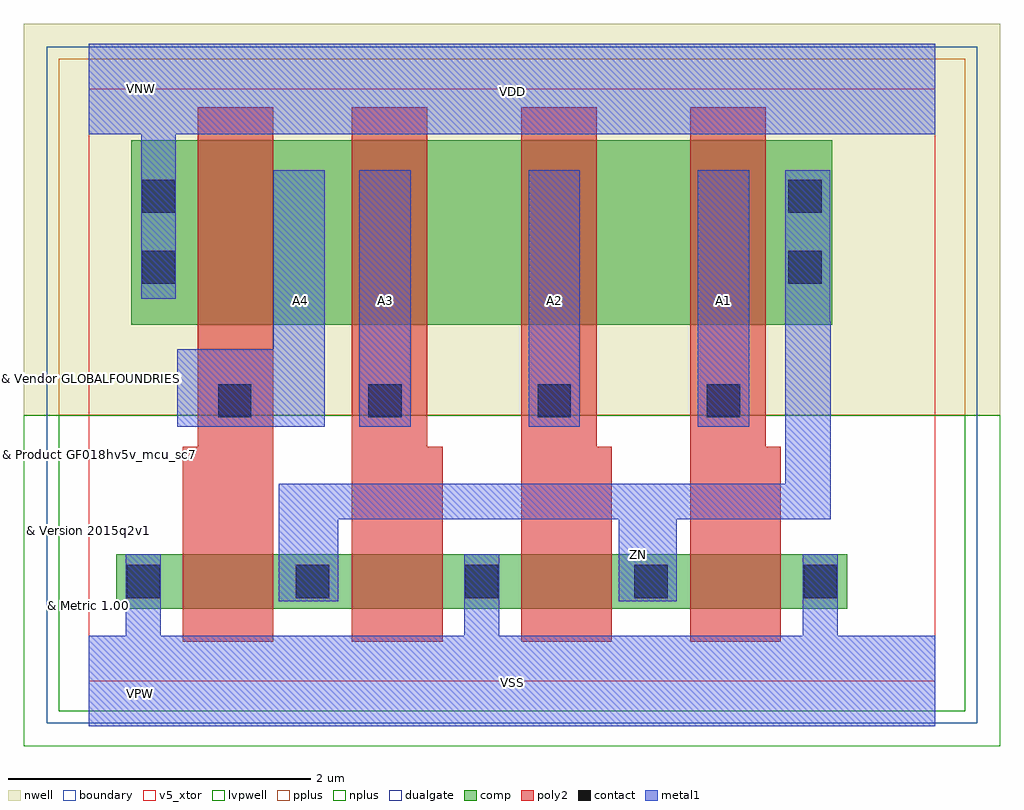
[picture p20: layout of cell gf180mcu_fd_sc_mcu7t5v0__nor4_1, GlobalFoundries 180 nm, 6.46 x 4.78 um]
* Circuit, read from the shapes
.subckt gf180mcu_fd_sc_mcu7t5v0__nor4_1 A1 A2 A3 A4 VDD VNW VSS ZN
XM1 ZN A4 VSS VSUBS nfet_05v0 w=0.36u l=0.6u
XM2 VSS A3 ZN VSUBS nfet_05v0 w=0.36u l=0.6u
XM3 ZN A2 VSS VSUBS nfet_05v0 w=0.36u l=0.6u
XM4 VSS A1 ZN VSUBS nfet_05v0 w=0.36u l=0.6u
XM5 n1 A4 VDD VNW pfet_05v0 w=1.22u l=0.5u
XM6 n2 A3 n1 VNW pfet_05v0 w=1.22u l=0.5u
XM7 n3 A2 n2 VNW pfet_05v0 w=1.22u l=0.5u
XM8 ZN A1 n3 VNW pfet_05v0 w=1.22u l=0.5u
.ends

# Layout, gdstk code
import gdstk
lib = gdstk.Library(unit=1e-6, precision=1e-09)
def R(c, l, rs):  # rectangles x0, y0, x1, y1
    for r in rs: c.add(gdstk.rectangle(r[:2], r[2:], *l))
def A(c, l, x, y, w, h, nx, ny, dx, dy):  # array of equal rectangles
    R(c, l, [(x+i*dx, y+j*dy, x+i*dx+w, y+j*dy+h) for i in range(nx) for j in range(ny)])
def P(c, l, *ps):  # polygons
    for p in ps: c.add(gdstk.Polygon(p, *l))
boundary = (0, 0)
nwell = (21, 0)
comp = (22, 0)
poly2 = (30, 0)
pplus = (31, 0)
nplus = (32, 0)
contact = (33, 0)
metal1 = (34, 0)
dualgate = (55, 0)
v5_xtor = (112, 1)
lvpwell = (204, 0)

gf180mcu_fd_sc_mcu7t5v0_ = lib.new_cell('gf180mcu_fd_sc_mcu7t5v0__nor4_1')
R(gf180mcu_fd_sc_mcu7t5v0_, boundary, [(0,0,5.6,3.92)])
R(gf180mcu_fd_sc_mcu7t5v0_, nwell, [(-0.43,1.76,6.03,4.35)])
R(gf180mcu_fd_sc_mcu7t5v0_, comp, [(0.18,0.48,5.02,0.84), (0.28,2.36,4.92,3.58)])
P(gf180mcu_fd_sc_mcu7t5v0_, poly2, [(0.62,0.26),(0.62,1.55),(0.72,1.55),(0.72,3.8),(1.22,3.8),(1.22,0.26)],
  [(1.74,0.26),(1.74,3.8),(2.24,3.8),(2.24,1.55),(2.34,1.55),(2.34,0.26)],
  [(2.86,0.26),(2.86,3.8),(3.36,3.8),(3.36,1.55),(3.46,1.55),(3.46,0.26)],
  [(3.98,0.26),(3.98,3.8),(4.48,3.8),(4.48,1.55),(4.58,1.55),(4.58,0.26)])
R(gf180mcu_fd_sc_mcu7t5v0_, pplus, [(-0.2,1.76,5.8,4.12)])
R(gf180mcu_fd_sc_mcu7t5v0_, nplus, [(-0.2,-0.2,5.8,1.76)])
A(gf180mcu_fd_sc_mcu7t5v0_, contact, 0.25, 0.55, 0.22, 0.22, 5, 1, 1.12, 0)
A(gf180mcu_fd_sc_mcu7t5v0_, contact, 1.85, 1.745, 0.22, 0.22, 3, 1, 1.12, 0)
R(gf180mcu_fd_sc_mcu7t5v0_, contact, [(0.855,1.745,1.075,1.965), (0.35,2.63,0.57,2.85), (4.63,2.63,4.85,2.85), (0.35,3.1,0.57,3.32), (4.63,3.1,4.85,3.32)])
A(gf180mcu_fd_sc_mcu7t5v0_, metal1, 1.79, 1.685, 0.34, 1.695, 3, 1, 1.12, 0)
P(gf180mcu_fd_sc_mcu7t5v0_, metal1, [(0.585,1.685),(0.585,2.195),(1.22,2.195),(1.22,3.38),(1.56,3.38),(1.56,1.685)],
  [(1.255,0.53),(1.255,1.305),(4.61,1.305),(4.61,3.38),(4.905,3.38),(4.905,2.38),(4.91,2.38),(4.91,1.07),(3.89,1.07),(3.89,0.53),(3.505,0.53),(3.505,1.07),(1.65,1.07),(1.65,0.53)],
  [(0,-0.3),(0,0.3),(0.245,0.3),(0.245,0.84),(0.475,0.84),(0.475,0.3),(2.485,0.3),(2.485,0.84),(2.715,0.84),(2.715,0.3),(4.725,0.3),(4.725,0.84),(4.955,0.84),(4.955,0.3),(5.6,0.3),(5.6,-0.3)],
  [(0.345,2.53),(0.345,3.62),(0,3.62),(0,4.22),(5.6,4.22),(5.6,3.62),(0.575,3.62),(0.575,2.53)])
R(gf180mcu_fd_sc_mcu7t5v0_, dualgate, [(-0.28,-0.28,5.88,4.2)])
R(gf180mcu_fd_sc_mcu7t5v0_, v5_xtor, [(0,0,5.6,3.92)])
R(gf180mcu_fd_sc_mcu7t5v0_, lvpwell, [(-0.43,-0.43,6.03,1.76)])
gf180mcu_fd_sc_mcu7t5v0_.add(gdstk.Label('A3', (1.96,2.52), layer=34, texttype=10))
gf180mcu_fd_sc_mcu7t5v0_.add(gdstk.Label('A4', (1.4,2.52), layer=34, texttype=10))
gf180mcu_fd_sc_mcu7t5v0_.add(gdstk.Label('VDD', (2.8,3.905), layer=34, texttype=10))
gf180mcu_fd_sc_mcu7t5v0_.add(gdstk.Label('VSS', (2.8,-0.01), layer=34, texttype=10))
gf180mcu_fd_sc_mcu7t5v0_.add(gdstk.Label('ZN', (3.64,0.84), layer=34, texttype=10))
gf180mcu_fd_sc_mcu7t5v0_.add(gdstk.Label('A1', (4.2,2.52), layer=34, texttype=10))
gf180mcu_fd_sc_mcu7t5v0_.add(gdstk.Label('A2', (3.08,2.52), layer=34, texttype=10))
gf180mcu_fd_sc_mcu7t5v0_.add(gdstk.Label('& Vendor GLOBALFOUNDRIES', (0,2), layer=63, texttype=63))
gf180mcu_fd_sc_mcu7t5v0_.add(gdstk.Label('& Product GF018hv5v_mcu_sc7', (0,1.5), layer=63, texttype=63))
gf180mcu_fd_sc_mcu7t5v0_.add(gdstk.Label('& Version 2015q2v1', (0,1), layer=63, texttype=63))
gf180mcu_fd_sc_mcu7t5v0_.add(gdstk.Label('& Metric 1.00', (0,0.5), layer=63, texttype=63))
gf180mcu_fd_sc_mcu7t5v0_.add(gdstk.Label('VNW', (0.345,3.92), layer=21, texttype=10))
gf180mcu_fd_sc_mcu7t5v0_.add(gdstk.Label('VPW', (0.34,-0.085), layer=204, texttype=10))

lib.write_gds('gf180mcu_fd_sc_mcu7t5v0__nor4_1.gds')
